VERSION 5.7 ;
  NOWIREEXTENSIONATPIN ON ;
  DIVIDERCHAR "/" ;
  BUSBITCHARS "[]" ;
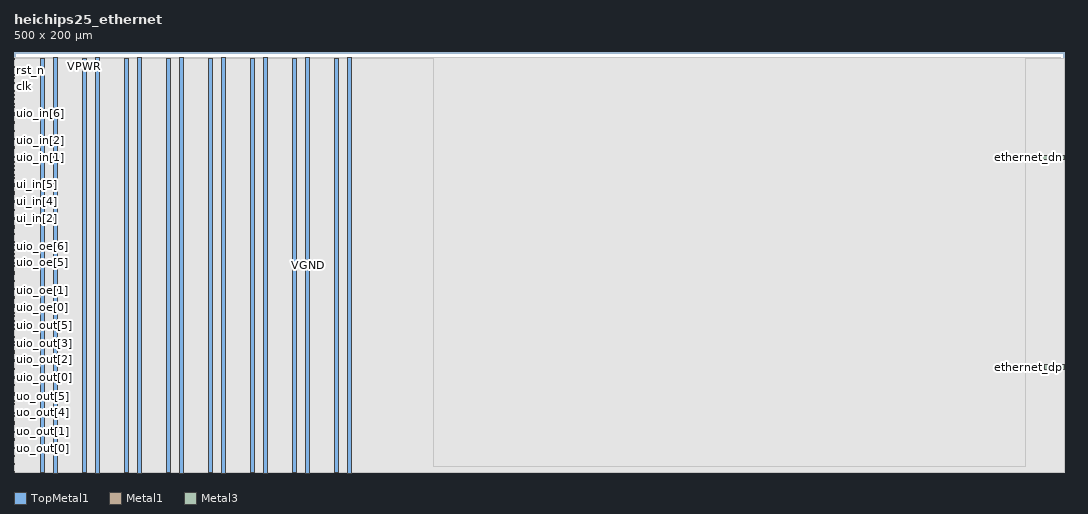
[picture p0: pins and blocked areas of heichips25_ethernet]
MACRO heichips25_ethernet
  CLASS BLOCK ;
  FOREIGN heichips25_ethernet ;
  ORIGIN 0.000 0.000 ;
  SIZE 500.000 BY 200.000 ;
  PIN VGND
    DIRECTION INOUT ;
    USE GROUND ;
    PORT
      LAYER TopMetal1 ;
        RECT 18.700 -0.630 20.900 197.190 ;
    END
    PORT
      LAYER TopMetal1 ;
        RECT 38.700 -0.630 40.900 197.190 ;
    END
    PORT
      LAYER TopMetal1 ;
        RECT 58.700 -0.630 60.900 197.190 ;
    END
    PORT
      LAYER TopMetal1 ;
        RECT 78.700 -0.630 80.900 197.190 ;
    END
    PORT
      LAYER TopMetal1 ;
        RECT 98.700 -0.630 100.900 197.190 ;
    END
    PORT
      LAYER TopMetal1 ;
        RECT 118.700 -0.630 120.900 197.190 ;
    END
    PORT
      LAYER TopMetal1 ;
        RECT 138.700 -0.630 140.900 197.190 ;
    END
    PORT
      LAYER TopMetal1 ;
        RECT 158.700 -0.630 160.900 197.190 ;
    END
    PORT
      LAYER Metal1 ;
        RECT 0.000 -0.220 0.160 0.220 ;
    END
    PORT
      LAYER Metal1 ;
        RECT 0.000 7.340 0.160 7.780 ;
    END
    PORT
      LAYER Metal1 ;
        RECT 0.000 14.900 0.160 15.340 ;
    END
    PORT
      LAYER Metal1 ;
        RECT 0.000 22.460 0.160 22.900 ;
    END
    PORT
      LAYER Metal1 ;
        RECT 0.000 30.020 0.160 30.460 ;
    END
    PORT
      LAYER Metal1 ;
        RECT 0.000 37.580 0.160 38.020 ;
    END
    PORT
      LAYER Metal1 ;
        RECT 0.000 45.140 0.160 45.580 ;
    END
    PORT
      LAYER Metal1 ;
        RECT 0.000 52.700 0.160 53.140 ;
    END
    PORT
      LAYER Metal1 ;
        RECT 0.000 60.260 0.160 60.700 ;
    END
    PORT
      LAYER Metal1 ;
        RECT 0.000 67.820 0.160 68.260 ;
    END
    PORT
      LAYER Metal1 ;
        RECT 0.000 75.380 0.160 75.820 ;
    END
    PORT
      LAYER Metal1 ;
        RECT 0.000 82.940 0.160 83.380 ;
    END
    PORT
      LAYER Metal1 ;
        RECT 0.000 90.500 0.160 90.940 ;
    END
    PORT
      LAYER Metal1 ;
        RECT 0.000 98.060 0.160 98.500 ;
    END
    PORT
      LAYER Metal1 ;
        RECT 0.000 105.620 0.160 106.060 ;
    END
    PORT
      LAYER Metal1 ;
        RECT 0.000 113.180 0.160 113.620 ;
    END
    PORT
      LAYER Metal1 ;
        RECT 0.000 120.740 0.160 121.180 ;
    END
    PORT
      LAYER Metal1 ;
        RECT 0.000 128.300 0.160 128.740 ;
    END
    PORT
      LAYER Metal1 ;
        RECT 0.000 135.860 0.160 136.300 ;
    END
    PORT
      LAYER Metal1 ;
        RECT 0.000 143.420 0.160 143.860 ;
    END
    PORT
      LAYER Metal1 ;
        RECT 0.000 150.980 0.160 151.420 ;
    END
    PORT
      LAYER Metal1 ;
        RECT 0.000 158.540 0.160 158.980 ;
    END
    PORT
      LAYER Metal1 ;
        RECT 0.000 166.100 0.160 166.540 ;
    END
    PORT
      LAYER Metal1 ;
        RECT 0.000 173.660 0.160 174.100 ;
    END
    PORT
      LAYER Metal1 ;
        RECT 0.000 181.220 0.160 181.660 ;
    END
    PORT
      LAYER Metal1 ;
        RECT 0.000 188.780 0.160 189.220 ;
    END
    PORT
      LAYER Metal1 ;
        RECT 0.000 196.340 0.160 196.780 ;
    END
  END VGND
  PIN VPWR
    DIRECTION INOUT ;
    USE POWER ;
    PORT
      LAYER TopMetal1 ;
        RECT 12.500 -0.220 14.700 196.780 ;
    END
    PORT
      LAYER TopMetal1 ;
        RECT 32.500 -0.220 34.700 196.780 ;
    END
    PORT
      LAYER TopMetal1 ;
        RECT 52.500 -0.220 54.700 196.780 ;
    END
    PORT
      LAYER TopMetal1 ;
        RECT 72.500 -0.220 74.700 196.780 ;
    END
    PORT
      LAYER TopMetal1 ;
        RECT 92.500 -0.220 94.700 196.780 ;
    END
    PORT
      LAYER TopMetal1 ;
        RECT 112.500 -0.220 114.700 196.780 ;
    END
    PORT
      LAYER TopMetal1 ;
        RECT 132.500 -0.220 134.700 196.780 ;
    END
    PORT
      LAYER TopMetal1 ;
        RECT 152.500 -0.220 154.700 196.780 ;
    END
    PORT
      LAYER Metal1 ;
        RECT 0.000 3.560 0.160 4.000 ;
    END
    PORT
      LAYER Metal1 ;
        RECT 0.000 11.120 0.160 11.560 ;
    END
    PORT
      LAYER Metal1 ;
        RECT 0.000 18.680 0.160 19.120 ;
    END
    PORT
      LAYER Metal1 ;
        RECT 0.000 26.240 0.160 26.680 ;
    END
    PORT
      LAYER Metal1 ;
        RECT 0.000 33.800 0.160 34.240 ;
    END
    PORT
      LAYER Metal1 ;
        RECT 0.000 41.360 0.160 41.800 ;
    END
    PORT
      LAYER Metal1 ;
        RECT 0.000 48.920 0.160 49.360 ;
    END
    PORT
      LAYER Metal1 ;
        RECT 0.000 56.480 0.160 56.920 ;
    END
    PORT
      LAYER Metal1 ;
        RECT 0.000 64.040 0.160 64.480 ;
    END
    PORT
      LAYER Metal1 ;
        RECT 0.000 71.600 0.160 72.040 ;
    END
    PORT
      LAYER Metal1 ;
        RECT 0.000 79.160 0.160 79.600 ;
    END
    PORT
      LAYER Metal1 ;
        RECT 0.000 86.720 0.160 87.160 ;
    END
    PORT
      LAYER Metal1 ;
        RECT 0.000 94.280 0.160 94.720 ;
    END
    PORT
      LAYER Metal1 ;
        RECT 0.000 101.840 0.160 102.280 ;
    END
    PORT
      LAYER Metal1 ;
        RECT 0.000 109.400 0.160 109.840 ;
    END
    PORT
      LAYER Metal1 ;
        RECT 0.000 116.960 0.160 117.400 ;
    END
    PORT
      LAYER Metal1 ;
        RECT 0.000 124.520 0.160 124.960 ;
    END
    PORT
      LAYER Metal1 ;
        RECT 0.000 132.080 0.160 132.520 ;
    END
    PORT
      LAYER Metal1 ;
        RECT 0.000 139.640 0.160 140.080 ;
    END
    PORT
      LAYER Metal1 ;
        RECT 0.000 147.200 0.160 147.640 ;
    END
    PORT
      LAYER Metal1 ;
        RECT 0.000 154.760 0.160 155.200 ;
    END
    PORT
      LAYER Metal1 ;
        RECT 0.000 162.320 0.160 162.760 ;
    END
    PORT
      LAYER Metal1 ;
        RECT 0.000 169.880 0.160 170.320 ;
    END
    PORT
      LAYER Metal1 ;
        RECT 0.000 177.440 0.160 177.880 ;
    END
    PORT
      LAYER Metal1 ;
        RECT 0.000 185.000 0.160 185.440 ;
    END
    PORT
      LAYER Metal1 ;
        RECT 0.000 192.560 0.160 193.000 ;
    END
  END VPWR
  PIN clk
    DIRECTION INPUT ;
    USE SIGNAL ;
    PORT
      LAYER Metal3 ;
        RECT 0.000 183.340 0.400 183.740 ;
    END
  END clk
  PIN ena
    DIRECTION INPUT ;
    USE SIGNAL ;
    PORT
      LAYER Metal3 ;
        RECT 0.000 179.140 0.400 179.540 ;
    END
  END ena
  PIN ethernet_dn
    DIRECTION OUTPUT ;
    USE SIGNAL ;
    ANTENNADIFFAREA 636.000000 ;
    PORT
      LAYER Metal3 ;
        RECT 487.485 148.940 500.000 150.940 ;
    END
  END ethernet_dn
  PIN ethernet_dp
    DIRECTION OUTPUT ;
    USE SIGNAL ;
    ANTENNADIFFAREA 636.000000 ;
    PORT
      LAYER Metal3 ;
        RECT 490.495 48.980 500.000 50.980 ;
    END
  END ethernet_dp
  PIN rst_n
    DIRECTION INPUT ;
    USE SIGNAL ;
    PORT
      LAYER Metal3 ;
        RECT 0.000 187.540 0.400 187.940 ;
    END
  END rst_n
  PIN ui_in[0]
    DIRECTION INPUT ;
    USE SIGNAL ;
    ANTENNAGATEAREA 0.180700 ;
    PORT
      LAYER Metal3 ;
        RECT 0.000 111.940 0.400 112.340 ;
    END
  END ui_in[0]
  PIN ui_in[1]
    DIRECTION INPUT ;
    USE SIGNAL ;
    PORT
      LAYER Metal3 ;
        RECT 0.000 116.140 0.400 116.540 ;
    END
  END ui_in[1]
  PIN ui_in[2]
    DIRECTION INPUT ;
    USE SIGNAL ;
    PORT
      LAYER Metal3 ;
        RECT 0.000 120.340 0.400 120.740 ;
    END
  END ui_in[2]
  PIN ui_in[3]
    DIRECTION INPUT ;
    USE SIGNAL ;
    PORT
      LAYER Metal3 ;
        RECT 0.000 124.540 0.400 124.940 ;
    END
  END ui_in[3]
  PIN ui_in[4]
    DIRECTION INPUT ;
    USE SIGNAL ;
    PORT
      LAYER Metal3 ;
        RECT 0.000 128.740 0.400 129.140 ;
    END
  END ui_in[4]
  PIN ui_in[5]
    DIRECTION INPUT ;
    USE SIGNAL ;
    PORT
      LAYER Metal3 ;
        RECT 0.000 132.940 0.400 133.340 ;
    END
  END ui_in[5]
  PIN ui_in[6]
    DIRECTION INPUT ;
    USE SIGNAL ;
    PORT
      LAYER Metal3 ;
        RECT 0.000 137.140 0.400 137.540 ;
    END
  END ui_in[6]
  PIN ui_in[7]
    DIRECTION INPUT ;
    USE SIGNAL ;
    PORT
      LAYER Metal3 ;
        RECT 0.000 141.340 0.400 141.740 ;
    END
  END ui_in[7]
  PIN uio_in[0]
    DIRECTION INPUT ;
    USE SIGNAL ;
    PORT
      LAYER Metal3 ;
        RECT 0.000 145.540 0.400 145.940 ;
    END
  END uio_in[0]
  PIN uio_in[1]
    DIRECTION INPUT ;
    USE SIGNAL ;
    PORT
      LAYER Metal3 ;
        RECT 0.000 149.740 0.400 150.140 ;
    END
  END uio_in[1]
  PIN uio_in[2]
    DIRECTION INPUT ;
    USE SIGNAL ;
    PORT
      LAYER Metal3 ;
        RECT 0.000 153.940 0.400 154.340 ;
    END
  END uio_in[2]
  PIN uio_in[3]
    DIRECTION INPUT ;
    USE SIGNAL ;
    PORT
      LAYER Metal3 ;
        RECT 0.000 158.140 0.400 158.540 ;
    END
  END uio_in[3]
  PIN uio_in[4]
    DIRECTION INPUT ;
    USE SIGNAL ;
    PORT
      LAYER Metal3 ;
        RECT 0.000 162.340 0.400 162.740 ;
    END
  END uio_in[4]
  PIN uio_in[5]
    DIRECTION INPUT ;
    USE SIGNAL ;
    PORT
      LAYER Metal3 ;
        RECT 0.000 166.540 0.400 166.940 ;
    END
  END uio_in[5]
  PIN uio_in[6]
    DIRECTION INPUT ;
    USE SIGNAL ;
    PORT
      LAYER Metal3 ;
        RECT 0.000 170.740 0.400 171.140 ;
    END
  END uio_in[6]
  PIN uio_in[7]
    DIRECTION INPUT ;
    USE SIGNAL ;
    PORT
      LAYER Metal3 ;
        RECT 0.000 174.940 0.400 175.340 ;
    END
  END uio_in[7]
  PIN uio_oe[0]
    DIRECTION OUTPUT ;
    USE SIGNAL ;
    ANTENNADIFFAREA 0.299200 ;
    PORT
      LAYER Metal3 ;
        RECT 0.000 78.340 0.400 78.740 ;
    END
  END uio_oe[0]
  PIN uio_oe[1]
    DIRECTION OUTPUT ;
    USE SIGNAL ;
    ANTENNADIFFAREA 0.299200 ;
    PORT
      LAYER Metal3 ;
        RECT 0.000 82.540 0.400 82.940 ;
    END
  END uio_oe[1]
  PIN uio_oe[2]
    DIRECTION OUTPUT ;
    USE SIGNAL ;
    ANTENNADIFFAREA 0.299200 ;
    PORT
      LAYER Metal3 ;
        RECT 0.000 86.740 0.400 87.140 ;
    END
  END uio_oe[2]
  PIN uio_oe[3]
    DIRECTION OUTPUT ;
    USE SIGNAL ;
    ANTENNADIFFAREA 0.299200 ;
    PORT
      LAYER Metal3 ;
        RECT 0.000 90.940 0.400 91.340 ;
    END
  END uio_oe[3]
  PIN uio_oe[4]
    DIRECTION OUTPUT ;
    USE SIGNAL ;
    ANTENNADIFFAREA 0.299200 ;
    PORT
      LAYER Metal3 ;
        RECT 0.000 95.140 0.400 95.540 ;
    END
  END uio_oe[4]
  PIN uio_oe[5]
    DIRECTION OUTPUT ;
    USE SIGNAL ;
    ANTENNADIFFAREA 0.299200 ;
    PORT
      LAYER Metal3 ;
        RECT 0.000 99.340 0.400 99.740 ;
    END
  END uio_oe[5]
  PIN uio_oe[6]
    DIRECTION OUTPUT ;
    USE SIGNAL ;
    ANTENNADIFFAREA 0.299200 ;
    PORT
      LAYER Metal3 ;
        RECT 0.000 103.540 0.400 103.940 ;
    END
  END uio_oe[6]
  PIN uio_oe[7]
    DIRECTION OUTPUT ;
    USE SIGNAL ;
    ANTENNADIFFAREA 0.299200 ;
    PORT
      LAYER Metal3 ;
        RECT 0.000 107.740 0.400 108.140 ;
    END
  END uio_oe[7]
  PIN uio_out[0]
    DIRECTION OUTPUT ;
    USE SIGNAL ;
    ANTENNADIFFAREA 0.299200 ;
    PORT
      LAYER Metal3 ;
        RECT 0.000 44.740 0.400 45.140 ;
    END
  END uio_out[0]
  PIN uio_out[1]
    DIRECTION OUTPUT ;
    USE SIGNAL ;
    ANTENNADIFFAREA 0.299200 ;
    PORT
      LAYER Metal3 ;
        RECT 0.000 48.940 0.400 49.340 ;
    END
  END uio_out[1]
  PIN uio_out[2]
    DIRECTION OUTPUT ;
    USE SIGNAL ;
    ANTENNADIFFAREA 0.299200 ;
    PORT
      LAYER Metal3 ;
        RECT 0.000 53.140 0.400 53.540 ;
    END
  END uio_out[2]
  PIN uio_out[3]
    DIRECTION OUTPUT ;
    USE SIGNAL ;
    ANTENNADIFFAREA 0.299200 ;
    PORT
      LAYER Metal3 ;
        RECT 0.000 57.340 0.400 57.740 ;
    END
  END uio_out[3]
  PIN uio_out[4]
    DIRECTION OUTPUT ;
    USE SIGNAL ;
    ANTENNADIFFAREA 0.299200 ;
    PORT
      LAYER Metal3 ;
        RECT 0.000 61.540 0.400 61.940 ;
    END
  END uio_out[4]
  PIN uio_out[5]
    DIRECTION OUTPUT ;
    USE SIGNAL ;
    ANTENNADIFFAREA 0.299200 ;
    PORT
      LAYER Metal3 ;
        RECT 0.000 65.740 0.400 66.140 ;
    END
  END uio_out[5]
  PIN uio_out[6]
    DIRECTION OUTPUT ;
    USE SIGNAL ;
    ANTENNADIFFAREA 0.299200 ;
    PORT
      LAYER Metal3 ;
        RECT 0.000 69.940 0.400 70.340 ;
    END
  END uio_out[6]
  PIN uio_out[7]
    DIRECTION OUTPUT ;
    USE SIGNAL ;
    ANTENNADIFFAREA 0.299200 ;
    PORT
      LAYER Metal3 ;
        RECT 0.000 74.140 0.400 74.540 ;
    END
  END uio_out[7]
  PIN uo_out[0]
    DIRECTION OUTPUT ;
    USE SIGNAL ;
    ANTENNADIFFAREA 0.299200 ;
    PORT
      LAYER Metal3 ;
        RECT 0.000 11.140 0.400 11.540 ;
    END
  END uo_out[0]
  PIN uo_out[1]
    DIRECTION OUTPUT ;
    USE SIGNAL ;
    ANTENNADIFFAREA 0.299200 ;
    PORT
      LAYER Metal3 ;
        RECT 0.000 15.340 0.400 15.740 ;
    END
  END uo_out[1]
  PIN uo_out[2]
    DIRECTION OUTPUT ;
    USE SIGNAL ;
    ANTENNADIFFAREA 0.299200 ;
    PORT
      LAYER Metal3 ;
        RECT 0.000 19.540 0.400 19.940 ;
    END
  END uo_out[2]
  PIN uo_out[3]
    DIRECTION OUTPUT ;
    USE SIGNAL ;
    ANTENNADIFFAREA 0.299200 ;
    PORT
      LAYER Metal3 ;
        RECT 0.000 23.740 0.400 24.140 ;
    END
  END uo_out[3]
  PIN uo_out[4]
    DIRECTION OUTPUT ;
    USE SIGNAL ;
    ANTENNADIFFAREA 0.299200 ;
    PORT
      LAYER Metal3 ;
        RECT 0.000 27.940 0.400 28.340 ;
    END
  END uo_out[4]
  PIN uo_out[5]
    DIRECTION OUTPUT ;
    USE SIGNAL ;
    ANTENNADIFFAREA 0.299200 ;
    PORT
      LAYER Metal3 ;
        RECT 0.000 32.140 0.400 32.540 ;
    END
  END uo_out[5]
  PIN uo_out[6]
    DIRECTION OUTPUT ;
    USE SIGNAL ;
    ANTENNADIFFAREA 0.299200 ;
    PORT
      LAYER Metal3 ;
        RECT 0.000 36.340 0.400 36.740 ;
    END
  END uo_out[6]
  PIN uo_out[7]
    DIRECTION OUTPUT ;
    USE SIGNAL ;
    ANTENNADIFFAREA 0.299200 ;
    PORT
      LAYER Metal3 ;
        RECT 0.000 40.540 0.400 40.940 ;
    END
  END uo_out[7]
  OBS
      LAYER GatPoly ;
        RECT 0.000 0.000 498.000 197.290 ;
      LAYER Metal1 ;
        RECT 0.160 196.960 498.110 197.150 ;
        RECT 0.340 196.160 498.110 196.960 ;
        RECT 0.160 193.180 498.110 196.160 ;
        RECT 0.340 192.380 498.110 193.180 ;
        RECT 0.160 189.400 498.110 192.380 ;
        RECT 0.340 188.600 498.110 189.400 ;
        RECT 0.160 185.620 498.110 188.600 ;
        RECT 0.340 184.820 498.110 185.620 ;
        RECT 0.160 181.840 498.110 184.820 ;
        RECT 0.340 181.040 498.110 181.840 ;
        RECT 0.160 178.060 498.110 181.040 ;
        RECT 0.340 177.260 498.110 178.060 ;
        RECT 0.160 174.280 498.110 177.260 ;
        RECT 0.340 173.480 498.110 174.280 ;
        RECT 0.160 170.500 498.110 173.480 ;
        RECT 0.340 169.700 498.110 170.500 ;
        RECT 0.160 166.720 498.110 169.700 ;
        RECT 0.340 165.920 498.110 166.720 ;
        RECT 0.160 162.940 498.110 165.920 ;
        RECT 0.340 162.140 498.110 162.940 ;
        RECT 0.160 159.160 498.110 162.140 ;
        RECT 0.340 158.360 498.110 159.160 ;
        RECT 0.160 155.380 498.110 158.360 ;
        RECT 0.340 154.580 498.110 155.380 ;
        RECT 0.160 151.600 498.110 154.580 ;
        RECT 0.340 150.800 498.110 151.600 ;
        RECT 0.160 147.820 498.110 150.800 ;
        RECT 0.340 147.020 498.110 147.820 ;
        RECT 0.160 144.040 498.110 147.020 ;
        RECT 0.340 143.240 498.110 144.040 ;
        RECT 0.160 140.260 498.110 143.240 ;
        RECT 0.340 139.460 498.110 140.260 ;
        RECT 0.160 136.480 498.110 139.460 ;
        RECT 0.340 135.680 498.110 136.480 ;
        RECT 0.160 132.700 498.110 135.680 ;
        RECT 0.340 131.900 498.110 132.700 ;
        RECT 0.160 128.920 498.110 131.900 ;
        RECT 0.340 128.120 498.110 128.920 ;
        RECT 0.160 125.140 498.110 128.120 ;
        RECT 0.340 124.340 498.110 125.140 ;
        RECT 0.160 121.360 498.110 124.340 ;
        RECT 0.340 120.560 498.110 121.360 ;
        RECT 0.160 117.580 498.110 120.560 ;
        RECT 0.340 116.780 498.110 117.580 ;
        RECT 0.160 113.800 498.110 116.780 ;
        RECT 0.340 113.000 498.110 113.800 ;
        RECT 0.160 110.020 498.110 113.000 ;
        RECT 0.340 109.220 498.110 110.020 ;
        RECT 0.160 106.240 498.110 109.220 ;
        RECT 0.340 105.440 498.110 106.240 ;
        RECT 0.160 102.460 498.110 105.440 ;
        RECT 0.340 101.660 498.110 102.460 ;
        RECT 0.160 98.680 498.110 101.660 ;
        RECT 0.340 97.880 498.110 98.680 ;
        RECT 0.160 94.900 498.110 97.880 ;
        RECT 0.340 94.100 498.110 94.900 ;
        RECT 0.160 91.120 498.110 94.100 ;
        RECT 0.340 90.320 498.110 91.120 ;
        RECT 0.160 87.340 498.110 90.320 ;
        RECT 0.340 86.540 498.110 87.340 ;
        RECT 0.160 83.560 498.110 86.540 ;
        RECT 0.340 82.760 498.110 83.560 ;
        RECT 0.160 79.780 498.110 82.760 ;
        RECT 0.340 78.980 498.110 79.780 ;
        RECT 0.160 76.000 498.110 78.980 ;
        RECT 0.340 75.200 498.110 76.000 ;
        RECT 0.160 72.220 498.110 75.200 ;
        RECT 0.340 71.420 498.110 72.220 ;
        RECT 0.160 68.440 498.110 71.420 ;
        RECT 0.340 67.640 498.110 68.440 ;
        RECT 0.160 64.660 498.110 67.640 ;
        RECT 0.340 63.860 498.110 64.660 ;
        RECT 0.160 60.880 498.110 63.860 ;
        RECT 0.340 60.080 498.110 60.880 ;
        RECT 0.160 57.100 498.110 60.080 ;
        RECT 0.340 56.300 498.110 57.100 ;
        RECT 0.160 53.320 498.110 56.300 ;
        RECT 0.340 52.520 498.110 53.320 ;
        RECT 0.160 49.540 498.110 52.520 ;
        RECT 0.340 48.740 498.110 49.540 ;
        RECT 0.160 45.760 498.110 48.740 ;
        RECT 0.340 44.960 498.110 45.760 ;
        RECT 0.160 41.980 498.110 44.960 ;
        RECT 0.340 41.180 498.110 41.980 ;
        RECT 0.160 38.200 498.110 41.180 ;
        RECT 0.340 37.400 498.110 38.200 ;
        RECT 0.160 34.420 498.110 37.400 ;
        RECT 0.340 33.620 498.110 34.420 ;
        RECT 0.160 30.640 498.110 33.620 ;
        RECT 0.340 29.840 498.110 30.640 ;
        RECT 0.160 26.860 498.110 29.840 ;
        RECT 0.340 26.060 498.110 26.860 ;
        RECT 0.160 23.080 498.110 26.060 ;
        RECT 0.340 22.280 498.110 23.080 ;
        RECT 0.160 19.300 498.110 22.280 ;
        RECT 0.340 18.500 498.110 19.300 ;
        RECT 0.160 15.520 498.110 18.500 ;
        RECT 0.340 14.720 498.110 15.520 ;
        RECT 0.160 11.740 498.110 14.720 ;
        RECT 0.340 10.940 498.110 11.740 ;
        RECT 0.160 7.960 498.110 10.940 ;
        RECT 0.340 7.160 498.110 7.960 ;
        RECT 0.160 4.180 498.110 7.160 ;
        RECT 0.340 3.380 498.110 4.180 ;
        RECT 0.160 0.400 498.110 3.380 ;
        RECT 0.340 0.080 498.110 0.400 ;
        RECT 0.160 0.000 498.110 0.080 ;
        RECT 0.160 -0.220 169.440 0.000 ;
      LAYER Metal2 ;
        RECT 0.325 0.000 498.110 196.705 ;
        RECT 18.880 -0.145 20.720 0.000 ;
        RECT 38.880 -0.145 40.720 0.000 ;
        RECT 58.880 -0.145 60.720 0.000 ;
        RECT 78.880 -0.145 80.720 0.000 ;
        RECT 98.880 -0.145 100.720 0.000 ;
        RECT 118.880 -0.145 120.720 0.000 ;
        RECT 138.880 -0.145 140.720 0.000 ;
        RECT 158.880 -0.145 160.720 0.000 ;
      LAYER Metal3 ;
        RECT 0.335 188.150 498.110 196.660 ;
        RECT 0.610 187.330 498.110 188.150 ;
        RECT 0.335 183.950 498.110 187.330 ;
        RECT 0.610 183.130 498.110 183.950 ;
        RECT 0.335 179.750 498.110 183.130 ;
        RECT 0.610 178.930 498.110 179.750 ;
        RECT 0.335 175.550 498.110 178.930 ;
        RECT 0.610 174.730 498.110 175.550 ;
        RECT 0.335 171.350 498.110 174.730 ;
        RECT 0.610 170.530 498.110 171.350 ;
        RECT 0.335 167.150 498.110 170.530 ;
        RECT 0.610 166.330 498.110 167.150 ;
        RECT 0.335 162.950 498.110 166.330 ;
        RECT 0.610 162.130 498.110 162.950 ;
        RECT 0.335 158.750 498.110 162.130 ;
        RECT 0.610 157.930 498.110 158.750 ;
        RECT 0.335 154.550 498.110 157.930 ;
        RECT 0.610 153.730 498.110 154.550 ;
        RECT 0.335 151.150 498.110 153.730 ;
        RECT 0.335 150.350 487.275 151.150 ;
        RECT 0.610 149.530 487.275 150.350 ;
        RECT 0.335 148.730 487.275 149.530 ;
        RECT 0.335 146.150 498.110 148.730 ;
        RECT 0.610 145.330 498.110 146.150 ;
        RECT 0.335 141.950 498.110 145.330 ;
        RECT 0.610 141.130 498.110 141.950 ;
        RECT 0.335 137.750 498.110 141.130 ;
        RECT 0.610 136.930 498.110 137.750 ;
        RECT 0.335 133.550 498.110 136.930 ;
        RECT 0.610 132.730 498.110 133.550 ;
        RECT 0.335 129.350 498.110 132.730 ;
        RECT 0.610 128.530 498.110 129.350 ;
        RECT 0.335 125.150 498.110 128.530 ;
        RECT 0.610 124.330 498.110 125.150 ;
        RECT 0.335 120.950 498.110 124.330 ;
        RECT 0.610 120.130 498.110 120.950 ;
        RECT 0.335 116.750 498.110 120.130 ;
        RECT 0.610 115.930 498.110 116.750 ;
        RECT 0.335 112.550 498.110 115.930 ;
        RECT 0.610 111.730 498.110 112.550 ;
        RECT 0.335 108.350 498.110 111.730 ;
        RECT 0.610 107.530 498.110 108.350 ;
        RECT 0.335 104.150 498.110 107.530 ;
        RECT 0.610 103.330 498.110 104.150 ;
        RECT 0.335 99.950 498.110 103.330 ;
        RECT 0.610 99.130 498.110 99.950 ;
        RECT 0.335 95.750 498.110 99.130 ;
        RECT 0.610 94.930 498.110 95.750 ;
        RECT 0.335 91.550 498.110 94.930 ;
        RECT 0.610 90.730 498.110 91.550 ;
        RECT 0.335 87.350 498.110 90.730 ;
        RECT 0.610 86.530 498.110 87.350 ;
        RECT 0.335 83.150 498.110 86.530 ;
        RECT 0.610 82.330 498.110 83.150 ;
        RECT 0.335 78.950 498.110 82.330 ;
        RECT 0.610 78.130 498.110 78.950 ;
        RECT 0.335 74.750 498.110 78.130 ;
        RECT 0.610 73.930 498.110 74.750 ;
        RECT 0.335 70.550 498.110 73.930 ;
        RECT 0.610 69.730 498.110 70.550 ;
        RECT 0.335 66.350 498.110 69.730 ;
        RECT 0.610 65.530 498.110 66.350 ;
        RECT 0.335 62.150 498.110 65.530 ;
        RECT 0.610 61.330 498.110 62.150 ;
        RECT 0.335 57.950 498.110 61.330 ;
        RECT 0.610 57.130 498.110 57.950 ;
        RECT 0.335 53.750 498.110 57.130 ;
        RECT 0.610 52.930 498.110 53.750 ;
        RECT 0.335 51.190 498.110 52.930 ;
        RECT 0.335 49.550 490.285 51.190 ;
        RECT 0.610 48.770 490.285 49.550 ;
        RECT 0.610 48.730 498.110 48.770 ;
        RECT 0.335 45.350 498.110 48.730 ;
        RECT 0.610 44.530 498.110 45.350 ;
        RECT 0.335 41.150 498.110 44.530 ;
        RECT 0.610 40.330 498.110 41.150 ;
        RECT 0.335 36.950 498.110 40.330 ;
        RECT 0.610 36.130 498.110 36.950 ;
        RECT 0.335 32.750 498.110 36.130 ;
        RECT 0.610 31.930 498.110 32.750 ;
        RECT 0.335 28.550 498.110 31.930 ;
        RECT 0.610 27.730 498.110 28.550 ;
        RECT 0.335 24.350 498.110 27.730 ;
        RECT 0.610 23.530 498.110 24.350 ;
        RECT 0.335 20.150 498.110 23.530 ;
        RECT 0.610 19.330 498.110 20.150 ;
        RECT 0.335 15.950 498.110 19.330 ;
        RECT 0.610 15.130 498.110 15.950 ;
        RECT 0.335 11.750 498.110 15.130 ;
        RECT 0.610 10.930 498.110 11.750 ;
        RECT 0.335 0.000 498.110 10.930 ;
        RECT 18.835 -0.100 20.765 0.000 ;
        RECT 38.835 -0.100 40.765 0.000 ;
        RECT 58.835 -0.100 60.765 0.000 ;
        RECT 78.835 -0.100 80.765 0.000 ;
        RECT 98.835 -0.100 100.765 0.000 ;
        RECT 118.835 -0.100 120.765 0.000 ;
        RECT 138.835 -0.100 140.765 0.000 ;
        RECT 158.835 -0.100 160.765 0.000 ;
      LAYER Metal4 ;
        RECT 0.380 0.000 498.110 196.705 ;
        RECT 18.880 -0.145 20.720 0.000 ;
        RECT 38.880 -0.145 40.720 0.000 ;
        RECT 58.880 -0.145 60.720 0.000 ;
        RECT 78.880 -0.145 80.720 0.000 ;
        RECT 98.880 -0.145 100.720 0.000 ;
        RECT 118.880 -0.145 120.720 0.000 ;
        RECT 138.880 -0.145 140.720 0.000 ;
        RECT 158.880 -0.145 160.720 0.000 ;
      LAYER Metal5 ;
        RECT 12.635 0.000 500.000 196.870 ;
        RECT 18.835 -0.310 20.765 0.000 ;
        RECT 38.835 -0.310 40.765 0.000 ;
        RECT 58.835 -0.310 60.765 0.000 ;
        RECT 78.835 -0.310 80.765 0.000 ;
        RECT 98.835 -0.310 100.765 0.000 ;
        RECT 118.835 -0.310 120.765 0.000 ;
        RECT 138.835 -0.310 140.765 0.000 ;
        RECT 158.835 -0.310 160.765 0.000 ;
      LAYER TopMetal1 ;
        RECT 199.840 2.470 481.840 197.530 ;
  END
END heichips25_ethernet
END LIBRARY

